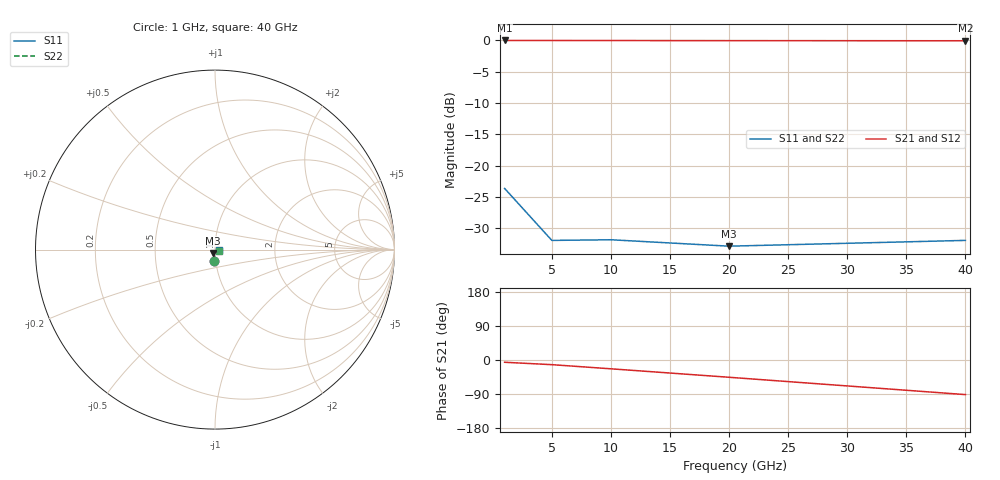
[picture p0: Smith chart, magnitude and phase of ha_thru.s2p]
! Generated by circuitRF - EM: Palace
! circuitRF-EM setup: ha_thru Palace
! circuitRF-EM layout: ha_thru.c3d
! circuitRF-EM written: 2026-11-04 15:33:56Z
! circuitRF-EM geometry: f21c1ac70043151b
! circuitRF-EM mesh: be36879526fbbc1a
! circuitRF-EM ports: 078653bfccbb427f
! circuitRF-EM model: Palace 0.18.1 (0dc74cd, schema 1-7-0)
! Port[1] = P1
! Port[2] = P2
! circuitRF-EM port 1: 'port/1' from 'airbox/zmin' to 'metal1', wave (mode 1), 50 Ohm: Palace's S is referred to the mode's own impedance Z_PV, renormalised here to 50 Ohm; reference plane 0 um into the structure from the port face
! circuitRF-EM port 2: 'port/2' from 'airbox/zmin' to 'metal1', wave (mode 1), 50 Ohm: Palace's S is referred to the mode's own impedance Z_PV, renormalised here to 50 Ohm; reference plane 0 um into the structure from the port face
! circuitRF-EM 3D mesh: 10,575 elements initially, 10,575 finally, 0 adaptive pass(es), element order 2
! circuitRF-EM 3D operating temperature: 20 C
! circuitRF-EM 3D run: preset Standard; 10575 -> 10575 tetrahedra; 74802 unknowns; 0 refinement pass(es); 5 frequency sample(s)
! circuitRF-EM 3D run cost: wall 39 s; Palace peak memory 1.6 GB
! circuitRF-EM 3D DC row: circuitRF conduction solve of the conductors, 370 elements, 0.17 s; ports as terminal pairs
! circuitRF-EM: re-running the EM setup rewrites this file. If circuitRF reports it as stale, the layout's cross-section changed after this file was written.
# GHz S RI R 50
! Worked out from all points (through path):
!   5 points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, 1 GHz to 40 GHz, reference 50 ohm
!   highest |S21| = -0.01 dB at 1 GHz (marker M1); lowest = -0.1 dB at 40 GHz (marker M2)
!   lowest |S11| = -32.8 dB at 20 GHz (marker M3), VSWR 1.05, Z = 48.6 - j1.79 ohm
!   |S11| at or under -10 dB: start of sweep to end of sweep
!   |S22| runs from -32.8 to -23.6 dB; largest |S21 - S12| = 1e-05
1  -0.00364 -0.0658  0.9932 -0.104  0.9932 -0.1041  -0.00364 -0.0658
5  -0.00355 -0.0251  0.975 -0.2128  0.975 -0.2128  -0.00353 -0.0251
10  -0.00775 -0.0245  0.916 -0.3935  0.916 -0.3935  -0.00766 -0.0245
20  -0.0136 -0.0184  0.6965 -0.7108  0.6965 -0.7108  -0.0133 -0.0186
40  0.0251 -0.00399  -0.0224 -0.9923  -0.0224 -0.9923  0.025 -0.00556
